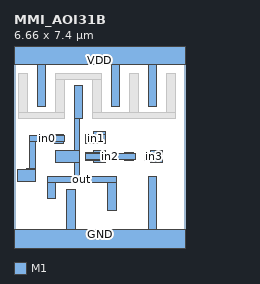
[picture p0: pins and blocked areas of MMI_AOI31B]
MACRO MMI_AOI31B
	CLASS CORE ;
	FOREIGN MMI_AOI31B 0 0 ;
	SIZE 6.66 BY 7.4 ;
	SYMMETRY X Y ;
	SITE CORE1 ;
	PIN out
		DIRECTION output ;
		USE SIGNAL ;
		PORT
			LAYER M1 ;
			RECT 2.34 4.81 2.68 6.09 ;
			LAYER M1 ;
			RECT 2.34 3.555 2.57 4.81 ;
			LAYER M1 ;
			RECT 1.625 3.105 2.57 3.555 ;
			LAYER M1 ;
			RECT 2.34 2.545 2.57 3.105 ;
			LAYER M1 ;
			RECT 1.295 2.315 3.98 2.545 ;
			LAYER M1 ;
			RECT 1.295 1.705 1.635 2.315 ;
			LAYER M1 ;
			RECT 3.64 1.245 3.98 2.315 ;
		END
		AntennaDiffArea 2.1804 ;
	END out
	PIN in1
		DIRECTION input ;
		USE SIGNAL ;
		PORT
			LAYER M1 ;
			RECT 3.105 4.19 3.555 4.295 ;
			LAYER M1 ;
			RECT 2.8 3.85 3.555 4.19 ;
			LAYER M1 ;
			RECT 3.105 3.845 3.555 3.85 ;
		END
		AntennaGateArea 1.1592 ;
	END in1
	PIN GND
		DIRECTION inout ;
		USE GROUND ;
		PORT
			LAYER M1 ;
			RECT 2.06 0.5 2.4 2.055 ;
			LAYER M1 ;
			RECT 5.22 0.5 5.56 2.545 ;
			LAYER M1 ;
			RECT 0 -0.5 6.66 0.5 ;
		END
	END GND
	PIN in2
		DIRECTION input ;
		USE SIGNAL ;
		PORT
			LAYER M1 ;
			RECT 3.105 3.5 3.555 3.555 ;
			LAYER M1 ;
			RECT 2.8 3.445 3.555 3.5 ;
			LAYER M1 ;
			RECT 4.31 3.445 4.65 3.5 ;
			LAYER M1 ;
			RECT 2.8 3.215 4.715 3.445 ;
			LAYER M1 ;
			RECT 2.8 3.16 3.555 3.215 ;
			LAYER M1 ;
			RECT 4.31 3.16 4.65 3.215 ;
			LAYER M1 ;
			RECT 3.105 3.105 3.555 3.16 ;
		END
		AntennaGateArea 1.1592 ;
	END in2
	PIN VDD
		DIRECTION inout ;
		USE POWER ;
		PORT
			LAYER M1 ;
			RECT 0 6.9 6.66 7.9 ;
			LAYER M1 ;
			RECT 0.9 5.29 1.24 6.9 ;
			LAYER M1 ;
			RECT 3.78 5.29 4.12 6.9 ;
			LAYER M1 ;
			RECT 5.22 5.29 5.56 6.9 ;
		END
	END VDD
	PIN in3
		DIRECTION input ;
		USE SIGNAL ;
		PORT
			LAYER M1 ;
			RECT 5.325 3.5 5.775 3.555 ;
			LAYER M1 ;
			RECT 5.1 3.16 5.775 3.5 ;
			LAYER M1 ;
			RECT 5.325 3.105 5.775 3.16 ;
		END
		AntennaGateArea 1.1592 ;
	END in3
	PIN in0
		DIRECTION input ;
		USE SIGNAL ;
		PORT
			LAYER M1 ;
			RECT 1.57 4.135 1.91 4.19 ;
			LAYER M1 ;
			RECT 0.595 3.905 1.975 4.135 ;
			LAYER M1 ;
			RECT 0.595 2.87 0.825 3.905 ;
			LAYER M1 ;
			RECT 1.57 3.85 1.91 3.905 ;
			LAYER M1 ;
			RECT 0.485 2.815 0.825 2.87 ;
			LAYER M1 ;
			RECT 0.145 2.365 0.825 2.815 ;
		END
		AntennaGateArea 0.828 ;
	END in0
	OBS
		LAYER M1 ;
		RECT 0.18 5.04 0.52 6.57 ;
		LAYER M1 ;
		RECT 1.62 6.34 3.4 6.57 ;
		LAYER M1 ;
		RECT 1.62 5.04 1.96 6.34 ;
		LAYER M1 ;
		RECT 0.18 4.81 1.96 5.04 ;
		LAYER M1 ;
		RECT 3.06 5.04 3.4 6.34 ;
		LAYER M1 ;
		RECT 4.5 5.04 4.84 6.57 ;
		LAYER M1 ;
		RECT 5.94 5.04 6.28 6.57 ;
		LAYER M1 ;
		RECT 3.06 4.81 6.28 5.04 ;
	END
END MMI_AOI31B
